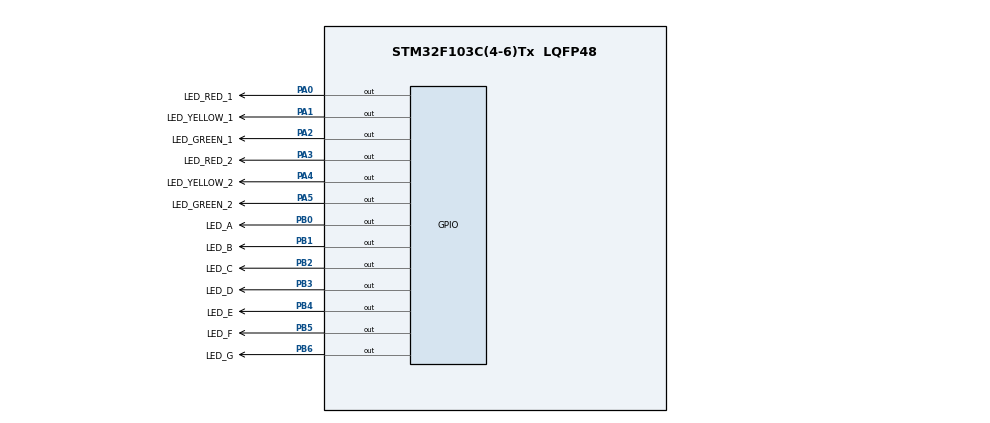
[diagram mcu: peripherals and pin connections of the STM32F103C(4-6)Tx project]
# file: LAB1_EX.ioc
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Mcu.Family=STM32F1
Mcu.Name=STM32F103C(4-6)Tx
Mcu.Package=LQFP48
NVIC.PriorityGroup=NVIC_PRIORITYGROUP_4
PA0-WKUP.GPIO_Label=LED_RED_1
PA0-WKUP.Signal=GPIO_Output
PA1.GPIO_Label=LED_YELLOW_1
PA1.Signal=GPIO_Output
PA2.GPIO_Label=LED_GREEN_1
PA2.Signal=GPIO_Output
PA3.GPIO_Label=LED_RED_2
PA3.Signal=GPIO_Output
PA4.GPIO_Label=LED_YELLOW_2
PA4.Signal=GPIO_Output
PA5.GPIO_Label=LED_GREEN_2
PA5.Signal=GPIO_Output
PB0.GPIO_Label=LED_A
PB0.Signal=GPIO_Output
PB1.GPIO_Label=LED_B
PB1.Signal=GPIO_Output
PB2.GPIO_Label=LED_C
PB2.Signal=GPIO_Output
PB3.GPIO_Label=LED_D
PB3.Signal=GPIO_Output
PB4.GPIO_Label=LED_E
PB4.Signal=GPIO_Output
PB5.GPIO_Label=LED_F
PB5.Signal=GPIO_Output
PB6.GPIO_Label=LED_G
PB6.Signal=GPIO_Output
ProjectManager.HeapSize=0x200
ProjectManager.StackSize=0x400
ProjectManager.TargetToolchain=STM32CubeIDE
RCC.APB1Freq_Value=8000000
RCC.APB2Freq_Value=8000000
VP_SYS_VS_ND.Mode=No_Debug
board=custom

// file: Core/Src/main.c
/* USER CODE BEGIN Header */
/**
  ******************************************************************************
  * @file           : main.c
  * @brief          : Main program body
  ******************************************************************************
  * @attention
  *
  * <h2><center>&copy; Copyright (c) 2023 STMicroelectronics.
  * All rights reserved.</center></h2>
  *
  * This software component is licensed by ST under BSD 3-Clause license,
  * the "License"; You may not use this file except in compliance with the
  * License. You may obtain a copy of the License at:
  *                        opensource.org/licenses/BSD-3-Clause
  *
  ******************************************************************************
  */
/* USER CODE END Header */
#include "main.h"

void SystemClock_Config(void);
static void MX_GPIO_Init(void);

/* USER CODE BEGIN 0 */
void clearAllClock(){
	HAL_GPIO_WritePin(LED0_GPIO_Port, LED0_Pin, RESET);
	HAL_GPIO_WritePin(LED1_GPIO_Port, LED1_Pin, RESET);
	HAL_GPIO_WritePin(LED2_GPIO_Port, LED2_Pin, RESET);
	HAL_GPIO_WritePin(LED3_GPIO_Port, LED3_Pin, RESET);
	HAL_GPIO_WritePin(LED4_GPIO_Port, LED4_Pin, RESET);
	HAL_GPIO_WritePin(LED5_GPIO_Port, LED5_Pin, RESET);
	HAL_GPIO_WritePin(LED6_GPIO_Port, LED6_Pin, RESET);
	HAL_GPIO_WritePin(LED7_GPIO_Port, LED7_Pin, RESET);
	HAL_GPIO_WritePin(LED8_GPIO_Port, LED8_Pin, RESET);
	HAL_GPIO_WritePin(LED9_GPIO_Port, LED9_Pin, RESET);
	HAL_GPIO_WritePin(LED10_GPIO_Port, LED10_Pin, RESET);
	HAL_GPIO_WritePin(LED11_GPIO_Port, LED11_Pin, RESET);
}

void setNumberOnClock(int num){
	switch(num){
	  case 0:
			  HAL_GPIO_WritePin(LED0_GPIO_Port, LED0_Pin, SET);
			  break;
	  case 1:
			  HAL_GPIO_WritePin(LED1_GPIO_Port, LED1_Pin, SET);
			  break;
	  case 2:
			  HAL_GPIO_WritePin(LED2_GPIO_Port, LED2_Pin, SET);
			  break;
	  case 3:
			  HAL_GPIO_WritePin(LED3_GPIO_Port, LED3_Pin, SET);
			  break;
	  case 4:
			  HAL_GPIO_WritePin(LED4_GPIO_Port, LED4_Pin, SET);
			  break;
	  case 5:
			  HAL_GPIO_WritePin(LED5_GPIO_Port, LED5_Pin, SET);
			  break;
	  case 6:
			  HAL_GPIO_WritePin(LED6_GPIO_Port, LED6_Pin, SET);
			  break;
	  case 7:
			  HAL_GPIO_WritePin(LED7_GPIO_Port, LED7_Pin, SET);
			  break;
	  case 8:
			  HAL_GPIO_WritePin(LED8_GPIO_Port, LED8_Pin, SET);
			  break;
	  case 9:
			  HAL_GPIO_WritePin(LED9_GPIO_Port, LED9_Pin, SET);
			  break;
	  case 10:
			  HAL_GPIO_WritePin(LED10_GPIO_Port, LED10_Pin, SET);
			  break;
	  case 11:
			  HAL_GPIO_WritePin(LED11_GPIO_Port, LED11_Pin, SET);
			  break;
	  default:
		  break;
	  }
}
void clearNumberOnClock(int num){
	switch(num){
	case 0:
		  HAL_GPIO_WritePin(LED0_GPIO_Port, LED0_Pin, RESET);
		  break;
	case 1:
		  HAL_GPIO_WritePin(LED1_GPIO_Port, LED1_Pin, RESET);
		  break;
	case 2:
		  HAL_GPIO_WritePin(LED2_GPIO_Port, LED2_Pin, RESET);
		  break;
	case 3:
		  HAL_GPIO_WritePin(LED3_GPIO_Port, LED3_Pin, RESET);
		  break;
	case 4:
		  HAL_GPIO_WritePin(LED4_GPIO_Port, LED4_Pin, RESET);
		  break;
	case 5:
		  HAL_GPIO_WritePin(LED5_GPIO_Port, LED5_Pin, RESET);
		  break;
	case 6:
		  HAL_GPIO_WritePin(LED6_GPIO_Port, LED6_Pin, RESET);
		  break;
	case 7:
		  HAL_GPIO_WritePin(LED7_GPIO_Port, LED7_Pin, RESET);
		  break;
	case 8:
		  HAL_GPIO_WritePin(LED8_GPIO_Port, LED8_Pin, RESET);
		  break;
	case 9:
		  HAL_GPIO_WritePin(LED9_GPIO_Port, LED9_Pin, RESET);
		  break;
	case 10:
		  HAL_GPIO_WritePin(LED10_GPIO_Port, LED10_Pin, RESET);
		  break;
	case 11:
		  HAL_GPIO_WritePin(LED11_GPIO_Port, LED11_Pin, RESET);
		  break;
	default:
		break;
	}
}
/* USER CODE END 0 */

int main(void)
{

  /* MCU Configuration--------------------------------------------------------*/

  /* Reset of all peripherals, Initializes the Flash interface and the Systick. */
  HAL_Init();

  /* Configure the system clock */
  SystemClock_Config();

  /* Initialize all configured peripherals */
  MX_GPIO_Init();

  /* Infinite loop */
  /* USER CODE BEGIN WHILE */
  int hour = 6, min = 59, sec = 50;
  while (1)
  {
    /* USER CODE END WHILE */

    /* USER CODE BEGIN 3 */
	  clearAllClock();

	  setNumberOnClock(sec/5);
	  setNumberOnClock(min/5);
	  setNumberOnClock(hour);
	  sec++;
	  if(sec >= 60){
		  sec = 0;
		  min++;
	  }
	  if(min >= 60){
		  min = 0;
		  hour++;
	  }
	  hour %= 12;
	  HAL_Delay(1000);
  }
  /* USER CODE END 3 */
}

void SystemClock_Config(void)
{
  RCC_OscInitTypeDef RCC_OscInitStruct = {0};
  RCC_ClkInitTypeDef RCC_ClkInitStruct = {0};

  /** Initializes the RCC Oscillators according to the specified parameters
  * in the RCC_OscInitTypeDef structure.
  */
  RCC_OscInitStruct.OscillatorType = RCC_OSCILLATORTYPE_HSI;
  RCC_OscInitStruct.HSIState = RCC_HSI_ON;
  RCC_OscInitStruct.HSICalibrationValue = RCC_HSICALIBRATION_DEFAULT;
  RCC_OscInitStruct.PLL.PLLState = RCC_PLL_NONE;
  if (HAL_RCC_OscConfig(&RCC_OscInitStruct) != HAL_OK)
  {
    Error_Handler();
  }
  /** Initializes the CPU, AHB and APB buses clocks
  */
  RCC_ClkInitStruct.ClockType = RCC_CLOCKTYPE_HCLK|RCC_CLOCKTYPE_SYSCLK
                              |RCC_CLOCKTYPE_PCLK1|RCC_CLOCKTYPE_PCLK2;
  RCC_ClkInitStruct.SYSCLKSource = RCC_SYSCLKSOURCE_HSI;
  RCC_ClkInitStruct.AHBCLKDivider = RCC_SYSCLK_DIV1;
  RCC_ClkInitStruct.APB1CLKDivider = RCC_HCLK_DIV1;
  RCC_ClkInitStruct.APB2CLKDivider = RCC_HCLK_DIV1;

  if (HAL_RCC_ClockConfig(&RCC_ClkInitStruct, FLASH_LATENCY_0) != HAL_OK)
  {
    Error_Handler();
  }
}

static void MX_GPIO_Init(void)
{
  GPIO_InitTypeDef GPIO_InitStruct = {0};

  /* GPIO Ports Clock Enable */
  __HAL_RCC_GPIOA_CLK_ENABLE();

  /*Configure GPIO pin Output Level */
  HAL_GPIO_WritePin(GPIOA, LED0_Pin|LED1_Pin|LED2_Pin|LED3_Pin
                          |LED4_Pin|LED5_Pin|LED6_Pin|LED7_Pin
                          |LED8_Pin|LED9_Pin|LED10_Pin|LED11_Pin, GPIO_PIN_RESET);

  /*Configure GPIO pins : LED0_Pin LED1_Pin LED2_Pin LED3_Pin
                           LED4_Pin LED5_Pin LED6_Pin LED7_Pin
                           LED8_Pin LED9_Pin LED10_Pin LED11_Pin */
  GPIO_InitStruct.Pin = LED0_Pin|LED1_Pin|LED2_Pin|LED3_Pin
                          |LED4_Pin|LED5_Pin|LED6_Pin|LED7_Pin
                          |LED8_Pin|LED9_Pin|LED10_Pin|LED11_Pin;
  GPIO_InitStruct.Mode = GPIO_MODE_OUTPUT_PP;
  GPIO_InitStruct.Pull = GPIO_NOPULL;
  GPIO_InitStruct.Speed = GPIO_SPEED_FREQ_LOW;
  HAL_GPIO_Init(GPIOA, &GPIO_InitStruct);

}

void Error_Handler(void)
{
  __disable_irq();
  while (1)
  {
  }
}

/************************ (C) COPYRIGHT STMicroelectronics *****END OF FILE****/
